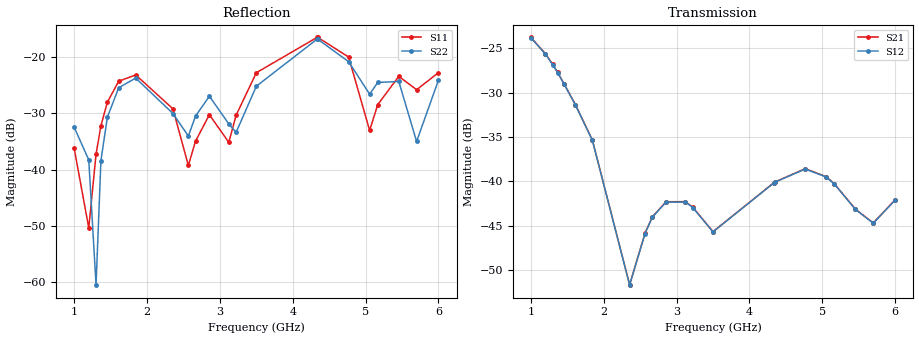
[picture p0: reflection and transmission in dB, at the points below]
!Agilent Technologies,E8364B,MY43040528,A.07.50.67
!Agilent E8364B: A.07.50.67
!Date: Sunday, March 01, 2026 22:13:36
!Correction: S11(Full 2 Port(1,2))
!S21(Full 2 Port(1,2))
!S12(Full 2 Port(1,2))
!S22(Full 2 Port(1,2))
!S2P File: Measurements: S11, S21, S12, S22:
# Hz S  dB  R 50
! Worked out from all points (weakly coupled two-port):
!   451 points, 1 GHz to 6 GHz, reference 50 ohm
!   highest |S21| = -23.77 dB at 1 GHz (marker M1); lowest = -51.7 dB at 2.356 GHz (marker M2)
!   lowest |S11| = -50.3 dB at 1.2 GHz (marker M3), VSWR 1.01, Z = 50.1 - j0.267 ohm
!   |S11| at or under -10 dB: start of sweep to end of sweep
!   |S22| runs from -60.5 to -16.9 dB; largest |S21 - S12| = 0.00026
!   S11 on the Smith chart (normalised r, x): 1 GHz: 1.03, +0.01; 4.333 GHz: 1.23, -0.24; 6 GHz: 0.98, -0.14
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1e9  -36.27 15.6  -23.77 154.9  -23.80 154.9  -32.52 -12.8
1.2e9  -50.33 -61.0  -25.62 40.9  -25.65 40.8  -38.29 -24.2
1.3e9  -37.28 -146.1  -26.81 -15.7  -26.85 -15.6  -60.47 -144.4
1.366667e9  -32.24 -165.4  -27.71 -52.8  -27.74 -52.7  -38.40 117.9
1.455556e9  -28.05 168.7  -29.00 -101.5  -29.03 -101.5  -30.72 90.9
1.611111e9  -24.35 131.2  -31.34 175.0  -31.38 175.0  -25.50 47.8
1.844444e9  -23.24 83.0  -35.35 51.1  -35.38 51.2  -23.80 -8.9
2.355556e9  -29.25 11.3  -51.65 -148.9  -51.70 -148.9  -30.08 -92.5
2.566667e9  -39.28 33.6  -45.85 152.0  -45.89 152.1  -34.06 -68.6
2.666667e9  -34.94 70.4  -44.01 103.8  -44.05 103.9  -30.51 -63.5
2.855556e9  -30.29 51.1  -42.30 6.9  -42.34 6.8  -27.01 -98.8
3.122222e9  -35.18 68.4  -42.29 -132.5  -42.33 -132.6  -31.92 -139.7
3.222222e9  -30.39 86.7  -42.91 176.2  -42.95 176.3  -33.42 -118.8
3.5e9  -22.85 54.9  -45.67 46.9  -45.70 46.8  -25.24 -129.5
4.333333e9  -16.60 -39.3  -40.17 29.0  -40.19 29.1  -16.91 113.6
4.344444e9  -16.59 -41.0  -40.09 23.1  -40.11 23.1  -16.92 111.3
4.766667e9  -20.07 -110.4  -38.57 148.4  -38.61 148.4  -20.89 32.8
5.055556e9  -33.07 -103.5  -39.48 -20.9  -39.52 -20.9  -26.65 34.6
5.166667e9  -28.50 -61.9  -40.28 -87.8  -40.31 -87.8  -24.57 33.4
5.455556e9  -23.49 -94.4  -43.14 87.7  -43.17 87.8  -24.40 -21.5
5.7e9  -25.86 -99.4  -44.69 -88.5  -44.72 -88.5  -35.02 -15.4
6e9  -22.84 -94.9  -42.08 59.2  -42.12 59.1  -24.17 -4.8
